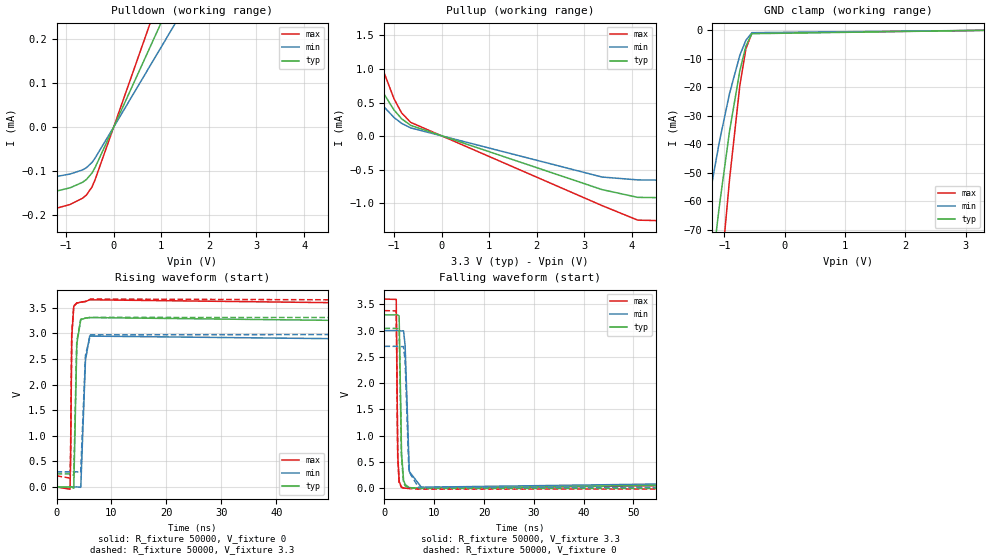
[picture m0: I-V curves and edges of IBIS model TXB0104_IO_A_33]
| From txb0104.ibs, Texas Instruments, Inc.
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[Model]   TXB0104_IO_A_33
Model_type  I/O
Vinl=1.05
Vinh=2.34
Enable   Active-High
Vref =   0
Rref =   1e6
Cref =   15p
Vmeas =   1.65
| variable   typ   min   max
C_comp   5.11pF   4.43pF   5.45pF
| C_pullup   5.02pF   4.36pF   5.51pF
| C_pulldown   14.55pF   4.28pF   26.43pF
| C_tri-state   5.11pF   4.43pF   5.45pF
[Temperature Range]   40   100   -40
| Ambient temperature   25   85   -40
[Voltage range]   3.3   3   3.6
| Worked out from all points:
|   slope of the pulldown table from 0 to 0.495 V, typ, clamps not added: 4.19 kohm
|   slope of the pullup table from 0 to 0.495 V, typ, clamps not added: 4.23 kohm
|   GND clamp passes 1 mA (typ) near -0.54 V on its own axis
|   rising waveform, R_fixture 50000, V_fixture 0: 20-80 % time 262ps typ, 409ps min, 160ps max; typ from 0 V to 3.04 V
|   falling waveform, R_fixture 50000, V_fixture 3.3: 20-80 % time 261ps typ, 426ps min, 157ps max; typ from 3.3 V to 0.255 V
|   rising waveform, R_fixture 50000, V_fixture 3.3: 20-80 % time 295ps typ, 477ps min, 177ps max; typ from 0.255 V to 3.3 V
|   falling waveform, R_fixture 50000, V_fixture 0: 20-80 % time 290ps typ, 493ps min, 170ps max; typ from 3.04 V to 0 V
[GND Clamp]
| TXB0104_IO_A_33
|   Voltage   I(typ)   I(min)   I(max)
-5.5V     -1.186A    -900.9mA   -1.496A
-1.505V   -142.8mA   -93.64mA   -207.1mA
-1.48V    -137.5mA   -90.01mA   -199.8mA
-1.28V    -97.16mA   -62.65mA   -143.3mA
-1.235V   -88.62mA   -56.95mA   -131.1mA
-1.095V   -63.56mA   -40.4mA    -94.59mA
-1.075V   -60.19mA   -38.2mA    -89.6mA
-915mV    -35.35mA   -22.13mA   -52.24mA
-745mV    -14.21mA   -8.785mA   -19.5mA
-645mV    -5.568mA   -3.533mA   -6.548mA
-545mV    -1.178mA   -831.4uA   -1.031mA
3.3V      578.4pA    2.059nA    114.1pA
[Pulldown]
| TXB0104_IO_A_33
|   Voltage   I(typ)   I(min)   I(max)
-5.5V     -201uA     -156.6uA   -254uA
-3.99V    -186.6uA   -145uA     -237uA
-3.24V    -178.5uA   -138.4uA   -225.9uA
-1.535V   -154.4uA   -119uA     -195uA
-915mV    -138.4uA   -107uA     -176.4uA
-655mV    -125.9uA   -97.65uA   -162.3uA
-575mV    -119.7uA   -92.78uA   -155.2uA
-455mV    -104.6uA   -80.59uA   -136.6uA
-390mV    -92.1uA    -70.66uA   -119.9uA
0V        0A         0A         0A
5.68V     1.356mA    1.039mA    1.757mA
11V       2.625mA    2.011mA    3.402mA
[Pullup]
| TXB0104_IO_A_33
|   Voltage   I(typ)   I(min)   I(max)
-5.5V     4.662mA    2.107mA    8.581mA
-2.08V    2.629mA    1.698mA    4.129mA
-1.795V   1.628mA    1.099mA    2.517mA
-1.545V   1.111mA    757.9uA    1.731mA
-1.455V   963.4uA    659.1uA    1.497mA
-1.265V   691uA      477.7uA    1.053mA
-1V       390.7uA    278.6uA    558uA
-840mV    259uA      190.8uA    346.3uA
-650mV    160.8uA    123uA      205.3uA
3.37V     -796uA     -609uA     -1.034mA
4.12V     -911.8uA   -651.7uA   -1.251mA
11V       -976uA     -694uA     -1.358mA
[Ramp]
| TXB0104_IO_A_33
| variable   typ   min   max
dV/dt_r   2.04/3.26E-10   1.85/5.13E-10   2.22/1.93E-10
dV/dt_f   1.98/3.10E-10   1.80/5.17E-10   2.17/1.81E-10
R_load = 50000
[Rising Waveform]
| TXB0104_IO_A_33
R_fixture =   50000
C_fixture =   0
L_fixture =   0
V_fixture =   0
V_fixture_min = 0
V_fixture_max = 0
|   Time   V(typ)   V(min)   V(max)
0s        551.6nV    2.491uV    61.57nV
2.455ns   -143.6uV   38.44uV    -42.57mV
2.555ns   -220.8uV   25uV       441mV
2.77ns    1.376mV    -1.284uV   2.929V
3.14ns    -25.58mV   -111.7uV   3.526V
3.695ns   2.797V     1.497mV    3.591V
4.415ns   3.269V     -6.216mV   3.609V
5.265ns   3.296V     2.475V     3.62V
6.03ns    3.308V     2.946V     3.655V
220ns     3.042V     2.702V     3.38V
[Falling Waveform]
| TXB0104_IO_A_33
R_fixture =   50000
C_fixture =   0
L_fixture =   0
V_fixture =   3.3
V_fixture_min = 3
V_fixture_max = 3.6
|   Time   V(typ)   V(min)   V(max)
0s        3.3V       3V         3.6V
2.37ns    3.3V       3V         3.593V
2.67ns    3.295V     3V         647.1mV
2.95ns    3.281V     3V         131.8mV
3.43ns    675.9mV    2.993V     21.09mV
3.845ns   152.4mV    2.995V     7.22mV
4.16ns    74.54mV    2.703V     2.855mV
4.995ns   13.58mV    320.5mV    -802.1uV
7.41ns    -597.1uV   20.49mV    1.577mV
220ns     255mV      295.2mV    218.5mV
[Rising Waveform]
| TXB0104_IO_A_33
R_fixture =   50000
C_fixture =   0
L_fixture =   0
V_fixture =   3.3
V_fixture_min = 3
V_fixture_max = 3.6
|   Time   V(typ)   V(min)   V(max)
0s        255mV      295.5mV    218.6mV
2.455ns   254.9mV    295.5mV    174.4mV
2.55ns    254.8mV    295.5mV    612.3mV
2.765ns   256.4mV    295.5mV    2.989V
3.14ns    227.9mV    295.3mV    3.537V
3.68ns    2.84V      296.9mV    3.592V
4.4ns     3.273V     281.5mV    3.61V
5.26ns    3.298V     2.565V     3.623V
6.175ns   3.311V     2.97V      3.669V
220ns     3.3V       3V         3.6V
[Falling Waveform]
| TXB0104_IO_A_33
R_fixture =   50000
C_fixture =   0
L_fixture =   0
V_fixture =   0
V_fixture_min = 0
V_fixture_max = 0
|   Time   V(typ)   V(min)   V(max)
0s        3.042V     2.701V     3.38V
2.37ns    3.042V     2.701V     3.374V
2.665ns   3.038V     2.701V     587.1mV
2.95ns    3.033V     2.701V     114.3mV
3.415ns   620.6mV    2.696V     19.2mV
3.82ns    113.3mV    2.697V     6.032mV
4.145ns   46.94mV    2.444V     1.509mV
4.915ns   7.318mV    320.5mV    -2.144mV
6.815ns   -2.645mV   20.02mV    -15.97mV
220ns     45.75uV    50.42uV    34.52uV
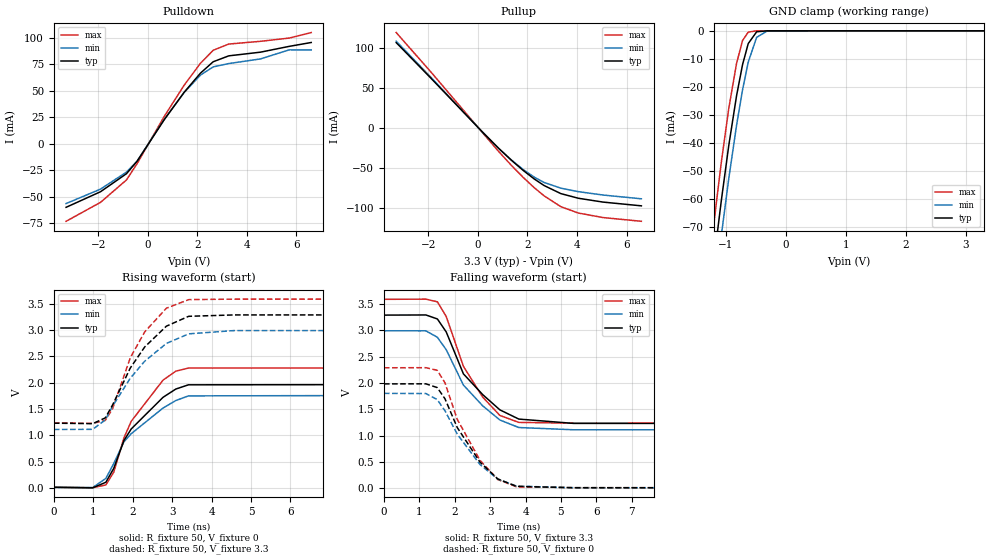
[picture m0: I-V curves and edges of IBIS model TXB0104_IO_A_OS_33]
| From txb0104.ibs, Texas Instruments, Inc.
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[Model]   TXB0104_IO_A_OS_33
Model_type  I/O
Vinl=1.05
Vinh=2.34
Enable   Active-High
Vref =   0
Rref =   1e6
Cref =   15p
Vmeas =   1.65
| variable   typ   min   max
C_comp   4.85pF   4.17pF   5.27pF
| C_pullup   4.75pF   3.50pF   6.19pF
| C_pulldown   5.01pF   4.72pF   5.56pF
| C_tri-state   4.85pF   4.17pF   5.27pF
[Temperature Range]   40   100   -40
| Ambient temperature   25   85   -40
[Voltage range]   3.3   3   3.6
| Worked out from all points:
|   slope of the pulldown table from 0 to 0.495 V, typ, clamps not added: 27.9 ohm
|   slope of the pullup table from 0 to 0.495 V, typ, clamps not added: 31.2 ohm
|   GND clamp passes 1 mA (typ) near -0.54 V on its own axis
|   rising waveform, R_fixture 50, V_fixture 0: 20-80 % time 1.04ns typ, 1.18ns min, 919ps max; typ from 0.014 V to 1.98 V
|   falling waveform, R_fixture 50, V_fixture 3.3: 20-80 % time 1.17ns typ, 1.14ns min, 979ps max; typ from 3.29 V to 1.23 V
|   rising waveform, R_fixture 50, V_fixture 3.3: 20-80 % time 1.02ns typ, 1.16ns min, 877ps max; typ from 1.23 V to 3.29 V
|   falling waveform, R_fixture 50, V_fixture 0: 20-80 % time 1.03ns typ, 1.09ns min, 968ps max; typ from 1.98 V to 0.014 V
[GND Clamp]
| TXB0104_IO_A_OS_33
|   Voltage   I(typ)   I(min)   I(max)
-3.3V     -587.8mA   -584.1mA   -608.8mA
-1.245V   -90.08mA   -102.8mA   -76.97mA
-1.215V   -84.5mA    -97.22mA   -71.21mA
-1.16V    -74.53mA   -87.19mA   -61mA
-1.08V    -60.7mA    -73.17mA   -47.04mA
-955mV    -40.93mA   -52.74mA   -27.71mA
-825mV    -23.18mA   -33.74mA   -11.63mA
-725mV    -12.08mA   -21.06mA   -3.466mA
-630mV    -4.553mA   -11.16mA   -461.2uA
-490mV    -357.3uA   -2.343mA   -5.283uA
-315mV    -3.31uA    -88.64uA   -3.916nA
3.3V      539.5pA    199.7nA    85.9pA
[Pulldown]
| TXB0104_IO_A_OS_33
|   Voltage   I(typ)   I(min)   I(max)
-3.3V     -60.02mA   -56.47mA   -73.23mA
-1.91V    -45.3mA    -42.83mA   -55.32mA
-860mV    -28.24mA   -26.73mA   -34.13mA
-430mV    -16.41mA   -16.29mA   -18.66mA
665mV     22.83mA    23.18mA    25.9mA
1.47V     48.74mA    48.5mA     55.44mA
2.13V     66.85mA    64.99mA    76.19mA
2.64V     77.52mA    72.68mA    88.35mA
3.27V     83.1mA     75.82mA    94.25mA
4.55V     86.58mA    80.19mA    96.83mA
5.71V     92.06mA    88.77mA    99.9mA
6.6V      95.72mA    88.73mA    105.1mA
[Pullup]
| TXB0104_IO_A_OS_33
|   Voltage   I(typ)   I(min)   I(max)
-3.3V     106.9mA    108.7mA    119.5mA
-1.895V   62.19mA    63.28mA    69.94mA
160mV     -4.428mA   -4.592mA   -5.078mA
835mV     -25.55mA   -25.63mA   -29.49mA
1.355V    -40.67mA   -40.32mA   -47.13mA
1.835V    -53.5mA    -52.37mA   -62.29mA
2.275V    -64.04mA   -61.75mA   -74.99mA
2.675V    -72.32mA   -68.47mA   -85.26mA
3.35V     -82.41mA   -75.55mA   -98.79mA
4.05V     -88.18mA   -79.91mA   -106.7mA
5.05V     -93.01mA   -84.16mA   -112.4mA
6.6V      -97.72mA   -88.91mA   -117.1mA
[Ramp]
| TXB0104_IO_A_OS_33
| variable   typ   min   max
dV/dt_r   1.19/1.04E-09   1.08/1.18E-09   1.37/9.20E-10
dV/dt_f   1.23/1.17E-09   1.13/1.14E-09   1.41/9.82E-10
R_load = 50
[Rising Waveform]
| TXB0104_IO_A_OS_33
R_fixture =   50
C_fixture =   0
L_fixture =   0
V_fixture =   0
V_fixture_min = 0
V_fixture_max = 0
|   Time   V(typ)   V(min)   V(max)
0s        13.75mV    11.49mV    14.78mV
985ps     2.733mV    8.31mV     5.237mV
1.32ns    109.1mV    182.4mV    57.84mV
1.52ns    372.6mV    464.2mV    301mV
1.78ns    902.7mV    878.5mV    953.5mV
1.965ns   1.122V     1.032V     1.268V
2.77ns    1.721V     1.517V     2.047V
3.095ns   1.878V     1.66V      2.217V
3.415ns   1.958V     1.748V     2.276V
39.94ns   1.982V     1.802V     2.287V
[Falling Waveform]
| TXB0104_IO_A_OS_33
R_fixture =   50
C_fixture =   0
L_fixture =   0
V_fixture =   3.3
V_fixture_min = 3
V_fixture_max = 3.6
|   Time   V(typ)   V(min)   V(max)
0s        3.285V     2.987V     3.584V
1.185ns   3.288V     2.987V     3.588V
1.51ns    3.212V     2.865V     3.537V
1.76ns    2.966V     2.629V     3.259V
2.245ns   2.172V     1.96V      2.314V
2.79ns    1.779V     1.566V     1.732V
3.275ns   1.49V      1.298V     1.384V
3.81ns    1.315V     1.155V     1.252V
5.36ns    1.233V     1.112V     1.237V
39.94ns   1.23V      1.111V     1.237V
[Rising Waveform]
| TXB0104_IO_A_OS_33
R_fixture =   50
C_fixture =   0
L_fixture =   0
V_fixture =   3.3
V_fixture_min = 3
V_fixture_max = 3.6
|   Time   V(typ)   V(min)   V(max)
0s        1.23V      1.111V     1.237V
985ps     1.221V     1.113V     1.226V
1.305ns   1.33V      1.292V     1.282V
1.49ns    1.575V     1.553V     1.505V
1.94ns    2.278V     2.085V     2.472V
2.305ns   2.676V     2.406V     2.962V
2.855ns   3.071V     2.743V     3.412V
3.42ns    3.258V     2.925V     3.575V
4.565ns   3.284V     2.987V     3.584V
39.94ns   3.285V     2.987V     3.584V
[Falling Waveform]
| TXB0104_IO_A_OS_33
R_fixture =   50
C_fixture =   0
L_fixture =   0
V_fixture =   0
V_fixture_min = 0
V_fixture_max = 0
|   Time   V(typ)   V(min)   V(max)
0s        1.982V     1.802V     2.287V
1.185ns   1.983V     1.799V     2.289V
1.505ns   1.912V     1.684V     2.24V
1.725ns   1.699V     1.472V     2.001V
2.07ns    1.156V     1.03V      1.312V
2.715ns   498.4mV    453.2mV    532.6mV
3.215ns   181.4mV    177.2mV    169.9mV
3.745ns   39.58mV    45.35mV    31.22mV
5.37ns    14.4mV     12.12mV    15.45mV
39.94ns   13.75mV    11.49mV    14.78mV
